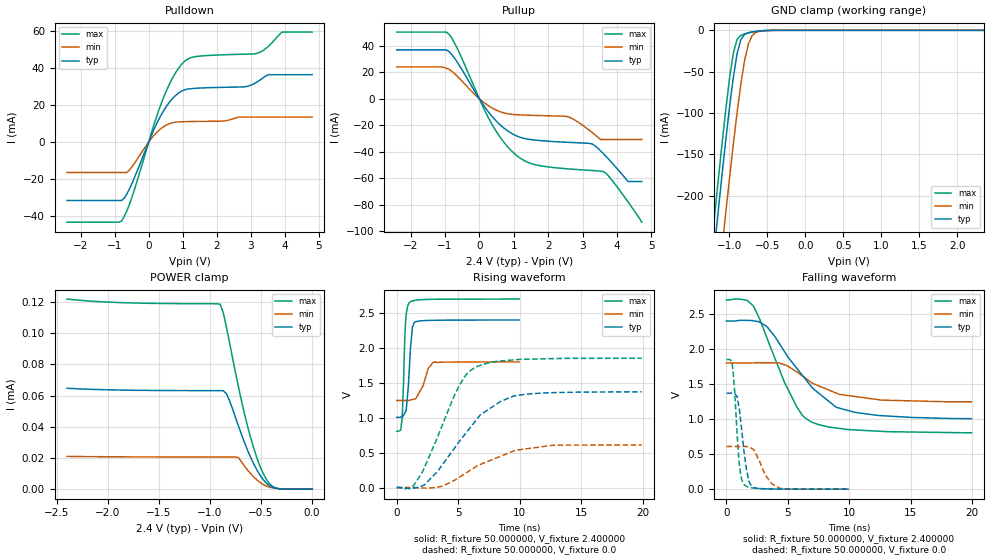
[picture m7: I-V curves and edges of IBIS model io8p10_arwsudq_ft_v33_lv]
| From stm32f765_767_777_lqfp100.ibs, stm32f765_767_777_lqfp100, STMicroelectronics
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|   Model io8p10_arwsudq_ft_v33_lv
[Model]  io8p10_arwsudq_ft_v33_lv
Model_type I/O
Polarity   Non-Inverting
Enable   Active-Low
Vinl =   0.720000V
Vinh =   1.680000V
Vmeas =  1.200000V
Cref =   40.000000pF
Rref =   100.000000M
Vref =   0.0V
C_comp   2.828400pF   2.771400pF   2.910300pF
[Temperature Range]   25.000000   0.125000k   -40.000000
[Pullup Reference]   2.400000V   1.800000V   2.700000V
[Pulldown Reference]   0.0V   0.0V   0.0V
[POWER Clamp Reference]   2.400000V   1.800000V   2.700000V
[GND Clamp Reference]   0.0V   0.0V   0.0V
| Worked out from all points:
|   slope of the pulldown table from 0 to 0.36 V, typ, clamps not added: 25 ohm
|   slope of the pullup table from 0 to 0.36 V, typ, clamps not added: 27.7 ohm
|   GND clamp passes 1 mA (typ) near -0.62 V on its own axis
|   rising waveform, R_fixture 50.000000, V_fixture 2.400000: 20-80 % time 323ps typ, 714ps min, 222ps max; typ from 1.01 V to 2.4 V
|   rising waveform, R_fixture 50.000000, V_fixture 0.0: 20-80 % time 3.77ns typ, 4.14ns min, 2.7ns max; typ from 0 V to 1.37 V
|   falling waveform, R_fixture 50.000000, V_fixture 2.400000: 20-80 % time 3.96ns typ, 3.55ns min, 2.75ns max; typ from 2.4 V to 1.01 V
|   falling waveform, R_fixture 50.000000, V_fixture 0.0: 20-80 % time 553ps typ, 1.05ns min, 408ps max; typ from 1.37 V to 0 V
[Pulldown]
|Voltage   I(typ)   I(min)   I(max)
-2.4V     -31.66mA   -16.51mA   -43.43mA
-800mV    -31.66mA   -16.51mA   -42.86mA
-480mV    -21.98mA   -13.17mA   -29.21mA
80mV      3.63mA     1.966mA    5.014mA
480mV     18.16mA    8.738mA    26.02mA
800mV     25.38mA    10.72mA    37.77mA
1.12V     28.53mA    11.02mA    44.6mA
2.8V      29.84mA    13.48mA    47.53mA
3.2V      32.65mA    13.48mA    48.04mA
3.52V     36.42mA    13.48mA    51.83mA
3.92V     36.42mA    13.48mA    59.49mA
4.8V      36.42mA    13.48mA    59.49mA
[Pullup]
|Voltage   I(typ)   I(min)   I(max)
-2.4V     36.9mA     24.04mA    50.34mA
-960mV    36.9mA     23.05mA    50.34mA
-640mV    27.65mA    17.04mA    37.98mA
320mV     -11.75mA   -6.207mA   -17.08mA
640mV     -20.52mA   -10.1mA    -30.35mA
960mV     -26.47mA   -11.82mA   -40.02mA
1.52V     -30.88mA   -12.51mA   -49.05mA
2.56V     -32.88mA   -13.49mA   -52.9mA
3.28V     -34.2mA    -25.51mA   -54.18mA
3.6V      -41.34mA   -30.76mA   -55mA
4.32V     -62.5mA    -30.76mA   -77.89mA
4.72V     -62.5mA    -30.76mA   -93.2mA
[GND_clamp]
|Voltage   I(typ)   I(min)   I(max)
-2.4V     -1.428A    -1.51A     -1.401A
-1.2V     -266.4mA   -356.3mA   -229.4mA
-1.15V    -221.3mA   -311mA     -184.1mA
-1.1V     -177.3mA   -266.4mA   -140mA
-1.05V    -134.8mA   -222.7mA   -97.97mA
-950mV    -58.22mA   -139.2mA   -28.55mA
-900mV    -29.03mA   -100.6mA   -11.27mA
-850mV    -11.41mA   -65.77mA   -6.067mA
-750mV    -2.852mA   -16.63mA   -3.179mA
-700mV    -1.914mA   -6.318mA   -2.181mA
-600mV    -750uA     -1.167mA   -738.3uA
2.35V     0A         0A         0A
[POWER_clamp]
|Voltage   I(typ)   I(min)   I(max)
-2.4V     64.71uA    21.03uA    121.9uA
-1.86V    63.55uA    20.74uA    119.6uA
-900mV    63.18uA    20.63uA    118.5uA
-870mV    63.14uA    20.63uA    113.2uA
-840mV    61.36uA    20.62uA    104.3uA
-720mV    40.37uA    20.18uA    65.28uA
-630mV    24.69uA    12.08uA    39.85uA
-540mV    12.26uA    5.907uA    20uA
-480mV    6.236uA    3.061uA    10.23uA
-420mV    2.4uA      1.365uA    3.726uA
-360mV    667.9nA    564nA      839.6nA
0V        0A         0A         0A
[Ramp]
| variable   typ   min   max
dV/dt_r  0.82212/3.77313n   0.36563/4.14209n   1.11144/2.69723n
dV/dt_f  0.83274/3.95762n   0.33408/3.60770n   1.13649/2.75428n
R_load = 50.000000
[Rising Waveform]
R_fixture= 50.000000
V_fixture= 2.400000
V_fixture_min= 1.800000
V_fixture_max= 2.700000
|time   V(typ)   V(min)   V(max)
0s        1.006V     1.247V     804.9mV
320.3ps   1.01V      1.247V     823.5mV
440.4ps   1.016V     1.247V     996.6mV
720.7ps   1.091V     1.247V     2.369V
940.9ps   1.444V     1.246V     2.622V
1.041ns   1.755V     1.249V     2.65V
1.281ns   2.298V     1.26V      2.673V
1.542ns   2.374V     1.271V     2.683V
2.963ns   2.395V     1.795V     2.697V
9.97ns    2.4V       1.8V       2.7V
[Rising Waveform]
R_fixture= 50.000000
V_fixture= 0.0
V_fixture_min= 0.0
V_fixture_max= 0.0
|time   V(typ)   V(min)   V(max)
0s        76.23uV    34.93uV    232.2uV
1.361ns   -8.154mV   -490.6uV   26.84mV
2.082ns   25.48mV    -6.757mV   218.5mV
4.765ns   580.8mV    110.6mV    1.347V
5.566ns   765.3mV    200.2mV    1.595V
6.326ns   935.3mV    285.3mV    1.713V
8.448ns   1.234V     447.6mV    1.812V
9.57ns    1.313V     527.4mV    1.829V
12.77ns   1.359V     606.5mV    1.847V
19.94ns   1.37V      609.1mV    1.851V
[Falling Waveform]
R_fixture= 50.000000
V_fixture= 2.400000
V_fixture_min= 1.800000
V_fixture_max= 2.700000
|time   V(typ)   V(min)   V(max)
0s        2.4V       1.8V       2.7V
1.522ns   2.41V      1.8V       2.7V
2.202ns   2.403V     1.802V     2.611V
3.283ns   2.322V     1.805V     2.165V
4.725ns   1.963V     1.775V     1.525V
6.166ns   1.628V     1.618V     1.055V
6.847ns   1.477V     1.532V     966.4mV
8.929ns   1.17V      1.372V     873.3mV
10.45ns   1.096V     1.323V     845.7mV
19.94ns   1.006V     1.247V     804.9mV
[Falling Waveform]
R_fixture= 50.000000
V_fixture= 0.0
V_fixture_min= 0.0
V_fixture_max= 0.0
|time   V(typ)   V(min)   V(max)
0s        1.37V      609.1mV    1.851V
460.5ps   1.371V     609mV      1.791V
660.7ps   1.366V     608.9mV    1.413V
1.041ns   1.153V     608.7mV    370.1mV
1.481ns   469.5mV    609.7mV    59.6mV
1.822ns   121.4mV    605.6mV    27.6mV
2.282ns   21.27mV    548.8mV    14.21mV
3.143ns   5.225mV    206.9mV    5.444mV
4.364ns   1.984mV    10.62mV    1.736mV
9.97ns    76.23uV    34.93uV    232.2uV
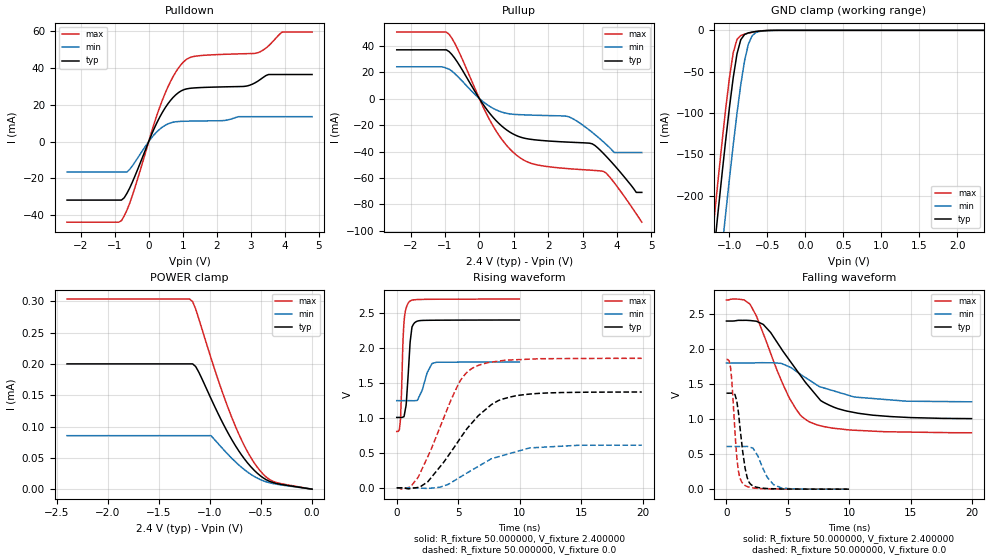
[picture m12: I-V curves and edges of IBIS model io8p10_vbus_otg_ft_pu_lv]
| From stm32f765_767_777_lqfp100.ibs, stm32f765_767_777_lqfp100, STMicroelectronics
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|   Model io8p10_vbus_otg_ft_pu_lv
[Model]  io8p10_vbus_otg_ft_pu_lv
Model_type I/O
Polarity   Non-Inverting
Enable   Active-Low
Vinl =   0.720000V
Vinh =   1.680000V
Vmeas =  1.200000V
Cref =   40.000000pF
Rref =   100.000000M
Vref =   0.0V
C_comp   3.193600pF   3.100000pF   3.332100pF
[Temperature Range]   25.000000   0.125000k   -40.000000
[Pullup Reference]   2.400000V   1.800000V   2.700000V
[Pulldown Reference]   0.0V   0.0V   0.0V
[POWER Clamp Reference]   2.400000V   1.800000V   2.700000V
[GND Clamp Reference]   0.0V   0.0V   0.0V
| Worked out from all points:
|   slope of the pulldown table from 0 to 0.36 V, typ, clamps not added: 25 ohm
|   slope of the pullup table from 0 to 0.36 V, typ, clamps not added: 27.7 ohm
|   GND clamp passes 1 mA (typ) near -0.61 V on its own axis
|   rising waveform, R_fixture 50.000000, V_fixture 2.400000: 20-80 % time 310ps typ, 633ps min, 223ps max; typ from 1.01 V to 2.4 V
|   rising waveform, R_fixture 50.000000, V_fixture 0.0: 20-80 % time 3.68ns typ, 4.27ns min, 2.69ns max; typ from 0.001 V to 1.37 V
|   falling waveform, R_fixture 50.000000, V_fixture 2.400000: 20-80 % time 3.54ns typ, 3.97ns min, 2.75ns max; typ from 2.4 V to 1.01 V
|   falling waveform, R_fixture 50.000000, V_fixture 0.0: 20-80 % time 575ps typ, 1.04ns min, 436ps max; typ from 1.37 V to 0.001 V
[Pulldown]
|Voltage   I(typ)   I(min)   I(max)
-2.4V     -31.69mA   -16.5mA    -43.66mA
-800mV    -31.69mA   -16.5mA    -42.82mA
-480mV    -21.96mA   -13.17mA   -29.19mA
80mV      3.63mA     1.966mA    5.014mA
480mV     18.16mA    8.738mA    26.02mA
800mV     25.38mA    10.72mA    37.77mA
1.12V     28.53mA    11.02mA    44.6mA
2.8V      29.84mA    13.46mA    47.53mA
3.2V      32.6mA     13.46mA    48.03mA
3.52V     36.28mA    13.46mA    51.75mA
3.92V     36.28mA    13.46mA    59.24mA
4.8V      36.28mA    13.46mA    59.24mA
[Pullup]
|Voltage   I(typ)   I(min)   I(max)
-2.4V     36.81mA    24.03mA    50.22mA
-960mV    36.81mA    23mA       50.22mA
-640mV    27.63mA    17.02mA    37.96mA
320mV     -11.75mA   -6.207mA   -17.08mA
960mV     -26.47mA   -11.82mA   -40.02mA
1.52V     -30.88mA   -12.51mA   -49.05mA
2.56V     -32.88mA   -13.49mA   -52.9mA
3.28V     -34.19mA   -25.52mA   -54.18mA
3.6V      -41.31mA   -32.62mA   -54.98mA
3.92V     -50.32mA   -40.8mA    -63.62mA
4.56V     -70.9mA    -40.8mA    -87.07mA
4.72V     -70.9mA    -40.8mA    -93.4mA
[GND_clamp]
|Voltage   I(typ)   I(min)   I(max)
-2.4V     -1.425A    -1.509A    -1.394A
-1.25V    -311.3mA   -401.9mA   -273.4mA
-1.2V     -265.5mA   -356.1mA   -227.3mA
-1.15V    -220.5mA   -310.9mA   -182mA
-1.1V     -176.4mA   -266.2mA   -138mA
-1.05V    -133.9mA   -222.5mA   -96.06mA
-950mV    -57.51mA   -139mA     -27.35mA
-900mV    -28.55mA   -100.5mA   -11.03mA
-850mV    -11.33mA   -65.67mA   -6.322mA
-750mV    -3.069mA   -16.69mA   -3.425mA
-600mV    -864.6uA   -1.294mA   -852.2uA
2.35V     0A         0A         0A
[POWER_clamp]
|Voltage   I(typ)   I(min)   I(max)
-2.4V     200uA      85.42uA    303.5uA
-1.2V     200uA      85.42uA    303.5uA
-1.17V    200uA      85.42uA    299.5uA
-1.14V    195.7uA    85.42uA    287.5uA
-990mV    144.6uA    85.42uA    209.3uA
-870mV    104.1uA    63.64uA    150.8uA
-780mV    77.28uA    48.22uA    111.8uA
-660mV    47.71uA    30.77uA    68.21uA
-570mV    30.64uA    20.64uA    42.8uA
-480mV    18.19uA    13.46uA    24.07uA
-390mV    10.91uA    9.255uA    13.01uA
0V        0A         0A         0A
[Ramp]
| variable   typ   min   max
dV/dt_r  0.82195/3.67216n   0.36569/4.26382n   1.11281/2.69174n
dV/dt_f  0.83256/3.54054n   0.33234/4.02440n   1.13575/2.74798n
R_load = 50.000000
[Rising Waveform]
R_fixture= 50.000000
V_fixture= 2.400000
V_fixture_min= 1.800000
V_fixture_max= 2.700000
|time   V(typ)   V(min)   V(max)
0s        1.007V     1.247V     805.7mV
300.3ps   1.007V     1.247V     974.6mV
520.5ps   1.013V     1.247V     2.148V
600.6ps   1.025V     1.247V     2.382V
760.8ps   1.18V      1.247V     2.568V
1.001ns   1.826V     1.247V     2.658V
1.241ns   2.3V       1.246V     2.683V
1.662ns   2.383V     1.25V      2.692V
2.883ns   2.396V     1.779V     2.696V
9.97ns    2.4V       1.8V       2.699V
[Rising Waveform]
R_fixture= 50.000000
V_fixture= 0.0
V_fixture_min= 0.0
V_fixture_max= 0.0
|time   V(typ)   V(min)   V(max)
0s        1.05mV     906.3uV    1.439mV
1.121ns   -9.416mV   968.2uV    17.09mV
1.762ns   8.574mV    -884.8uV   158.4mV
2.563ns   95.07mV    -5.947mV   460.3mV
5.045ns   677mV      141.8mV    1.492V
6.206ns   946mV      263.4mV    1.716V
7.728ns   1.193V     418.3mV    1.799V
9.69ns    1.317V     516mV      1.832V
14.81ns   1.367V     609.5mV    1.85V
19.94ns   1.371V     610.2mV    1.852V
[Falling Waveform]
R_fixture= 50.000000
V_fixture= 2.400000
V_fixture_min= 1.800000
V_fixture_max= 2.700000
|time   V(typ)   V(min)   V(max)
0s        2.4V       1.8V       2.699V
1.441ns   2.41V      1.8V       2.7V
1.922ns   2.407V     1.801V     2.64V
3.003ns   2.35V      1.805V     2.217V
5.125ns   1.841V     1.746V     1.299V
6.006ns   1.627V     1.642V     1.06V
6.687ns   1.471V     1.563V     967.9mV
7.688ns   1.263V     1.458V     903.8mV
9.77ns    1.116V     1.349V     850.2mV
19.94ns   1.007V     1.247V     805.7mV
[Falling Waveform]
R_fixture= 50.000000
V_fixture= 0.0
V_fixture_min= 0.0
V_fixture_max= 0.0
|time   V(typ)   V(min)   V(max)
0s        1.371V     610.2mV    1.852V
340.3ps   1.371V     610.2mV    1.726V
840.8ps   1.26V      610mV      466.1mV
1.061ns   952.1mV    609.7mV    186.2mV
1.381ns   465.5mV    610mV      71.93mV
1.702ns   158.6mV    610.5mV    37.53mV
2.302ns   35.97mV    546.3mV    15.49mV
3.323ns   9.552mV    169.8mV    5.369mV
4.464ns   3.586mV    18.95mV    2.839mV
9.97ns    1.05mV     906.3uV    1.439mV
